VERSION 5.8 ;
BUSBITCHARS "[]" ;
DIVIDERCHAR "/" ;
UNITS
    DATABASE MICRONS 1000 ;
END UNITS

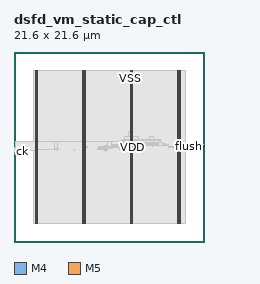
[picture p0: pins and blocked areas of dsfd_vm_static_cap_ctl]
MACRO dsfd_vm_static_cap_ctl
  FOREIGN dsfd_vm_static_cap_ctl 0 0 ;
  CLASS BLOCK ;
  SIZE 21.6 BY 21.6 ;
  PIN ck
    DIRECTION INPUT ;
    USE SIGNAL ;
    PORT
      LAYER M4 ;
        RECT  0 10.32 0.084 10.344 ;
    END
  END ck
  PIN flush
    DIRECTION OUTPUT ;
    USE SIGNAL ;
    PORT
      LAYER M4 ;
        RECT  21.516 10.8 21.6 10.824 ;
    END
  END flush
  PIN rn
    DIRECTION OUTPUT ;
    USE SIGNAL ;
    PORT
      LAYER M4 ;
        RECT  21.516 10.896 21.6 10.92 ;
    END
  END rn
  PIN rst_n
    DIRECTION INPUT ;
    USE SIGNAL ;
    PORT
      LAYER M4 ;
        RECT  0 10.416 0.084 10.44 ;
    END
  END rst_n
  PIN s_flt
    DIRECTION OUTPUT ;
    USE SIGNAL ;
    PORT
      LAYER M4 ;
        RECT  21.516 10.992 21.6 11.016 ;
    END
  END s_flt
  PIN st_drn
    DIRECTION INPUT ;
    USE SIGNAL ;
    PORT
      LAYER M4 ;
        RECT  0 10.512 0.084 10.536 ;
    END
  END st_drn
  PIN st_flt
    DIRECTION INPUT ;
    USE SIGNAL ;
    PORT
      LAYER M4 ;
        RECT  0 10.608 0.084 10.632 ;
    END
  END st_flt
  PIN st_live
    DIRECTION INPUT ;
    USE SIGNAL ;
    PORT
      LAYER M4 ;
        RECT  0 10.704 0.084 10.728 ;
    END
  END st_live
  PIN VDD
    DIRECTION INOUT ;
    USE POWER ;
    PORT
      LAYER M5 ;
        RECT  18.792 2.151 18.912 19.449 ;
        RECT  13.392 2.151 13.512 19.449 ;
        RECT  7.992 2.151 8.112 19.449 ;
        RECT  2.592 2.151 2.712 19.449 ;
    END
  END VDD
  PIN VSS
    DIRECTION INOUT ;
    USE GROUND ;
    PORT
      LAYER M5 ;
        RECT  18.6 2.137 18.72 19.463 ;
        RECT  13.2 2.137 13.32 19.463 ;
        RECT  7.8 2.137 7.92 19.463 ;
        RECT  2.4 2.137 2.52 19.463 ;
    END
  END VSS
  # OT_OBS_CLOSED layer=M5 d_um=1.536 added=0
  OBS
    LAYER RVTN ;
     RECT  2.16 2.16 19.44 2.295 ;
     RECT  2.16 2.565 19.44 2.835 ;
     RECT  2.16 3.105 19.44 3.375 ;
     RECT  2.16 3.645 19.44 3.915 ;
     RECT  2.16 4.185 19.44 4.455 ;
     RECT  2.16 4.725 19.44 4.995 ;
     RECT  2.16 5.265 19.44 5.535 ;
     RECT  2.16 5.805 19.44 6.075 ;
     RECT  2.16 6.345 19.44 6.615 ;
     RECT  2.16 6.885 19.44 7.155 ;
     RECT  2.16 7.425 19.44 7.695 ;
     RECT  2.16 7.965 19.44 8.235 ;
     RECT  2.16 8.505 19.44 8.775 ;
     RECT  2.16 9.045 19.44 9.315 ;
     RECT  2.16 9.585 19.44 9.855 ;
     RECT  2.16 10.125 19.44 10.395 ;
     RECT  2.16 10.665 19.44 10.935 ;
     RECT  2.16 11.205 19.44 11.475 ;
     RECT  2.16 11.745 19.44 12.015 ;
     RECT  2.16 12.285 19.44 12.555 ;
     RECT  2.16 12.825 19.44 13.095 ;
     RECT  2.16 13.365 19.44 13.635 ;
     RECT  2.16 13.905 19.44 14.175 ;
     RECT  2.16 14.445 19.44 14.715 ;
     RECT  2.16 14.985 19.44 15.255 ;
     RECT  2.16 15.525 19.44 15.795 ;
     RECT  2.16 16.065 19.44 16.335 ;
     RECT  2.16 16.605 19.44 16.875 ;
     RECT  2.16 17.145 19.44 17.415 ;
     RECT  2.16 17.685 19.44 17.955 ;
     RECT  2.16 18.225 19.44 18.495 ;
     RECT  2.16 18.765 19.44 19.035 ;
     RECT  2.16 19.305 19.44 19.44 ;
    LAYER RVTP ;
     RECT  2.16 2.295 19.44 2.565 ;
     RECT  2.16 2.835 19.44 3.105 ;
     RECT  2.16 3.375 19.44 3.645 ;
     RECT  2.16 3.915 19.44 4.185 ;
     RECT  2.16 4.455 19.44 4.725 ;
     RECT  2.16 4.995 19.44 5.265 ;
     RECT  2.16 5.535 19.44 5.805 ;
     RECT  2.16 6.075 19.44 6.345 ;
     RECT  2.16 6.615 19.44 6.885 ;
     RECT  2.16 7.155 19.44 7.425 ;
     RECT  2.16 7.695 19.44 7.965 ;
     RECT  2.16 8.235 19.44 8.505 ;
     RECT  2.16 8.775 19.44 9.045 ;
     RECT  2.16 9.315 19.44 9.585 ;
     RECT  2.16 9.855 19.44 10.125 ;
     RECT  2.16 10.395 19.44 10.665 ;
     RECT  2.16 10.935 19.44 11.205 ;
     RECT  2.16 11.475 19.44 11.745 ;
     RECT  2.16 12.015 19.44 12.285 ;
     RECT  2.16 12.555 19.44 12.825 ;
     RECT  2.16 13.095 19.44 13.365 ;
     RECT  2.16 13.635 19.44 13.905 ;
     RECT  2.16 14.175 19.44 14.445 ;
     RECT  2.16 14.715 19.44 14.985 ;
     RECT  2.16 15.255 19.44 15.525 ;
     RECT  2.16 15.795 19.44 16.065 ;
     RECT  2.16 16.335 19.44 16.605 ;
     RECT  2.16 16.875 19.44 17.145 ;
     RECT  2.16 17.415 19.44 17.685 ;
     RECT  2.16 17.955 19.44 18.225 ;
     RECT  2.16 18.495 19.44 18.765 ;
     RECT  2.16 19.035 19.44 19.305 ;
    LAYER M1 ;
     RECT  2.16 2.151 19.44 19.449 ;
    LAYER M2 ;
     RECT  2.16 2.151 19.44 19.449 ;
     RECT  19.44 10.746 20.543 11.034 ;
     RECT  20.543 11.016 21.515 11.034 ;
    LAYER M3 ;
     RECT  2.415 2.143 2.505 2.413 ;
     RECT  7.815 2.143 7.905 2.413 ;
     RECT  13.215 2.143 13.305 2.413 ;
     RECT  18.615 2.143 18.705 2.413 ;
     RECT  13.215 2.413 13.497 10.327 ;
     RECT  10.44 10.327 10.458 10.399 ;
     RECT  13.104 10.327 13.497 10.399 ;
     RECT  2.415 2.413 2.697 10.411 ;
     RECT  10.26 10.399 10.458 10.435 ;
     RECT  2.304 10.411 2.697 10.459 ;
     RECT  4.824 10.435 4.842 10.459 ;
     RECT  4.608 10.459 4.842 10.471 ;
     RECT  10.26 10.435 10.602 10.471 ;
     RECT  13.068 10.399 13.497 10.471 ;
     RECT  2.304 10.459 2.79 10.499 ;
     RECT  6.84 10.363 6.858 10.499 ;
     RECT  4.608 10.471 5.094 10.589 ;
     RECT  11.988 10.471 13.497 10.597 ;
     RECT  2.304 10.499 2.697 10.625 ;
     RECT  9.468 10.471 10.602 10.625 ;
     RECT  9.576 10.625 10.602 10.633 ;
     RECT  4.608 10.589 4.914 10.637 ;
     RECT  9.576 10.633 10.638 10.669 ;
     RECT  7.815 2.413 8.097 10.705 ;
     RECT  11.988 10.597 13.986 10.705 ;
     RECT  9.576 10.669 11.142 10.741 ;
     RECT  11.988 10.705 14.238 10.741 ;
     RECT  18.615 2.413 18.897 10.741 ;
     RECT  9.576 10.741 14.238 10.831 ;
     RECT  7.815 10.705 8.406 10.859 ;
     RECT  17.568 10.741 18.897 10.859 ;
     RECT  20.52 10.741 20.538 10.891 ;
     RECT  4.248 10.699 4.266 10.895 ;
     RECT  9.576 10.831 14.85 10.895 ;
     RECT  10.26 10.895 14.85 10.931 ;
     RECT  20.484 10.891 20.538 10.931 ;
     RECT  15.768 10.831 15.786 10.933 ;
     RECT  15.768 10.933 15.858 10.939 ;
     RECT  17.568 10.859 17.586 10.939 ;
     RECT  15.768 10.939 16.47 10.975 ;
     RECT  17.424 10.939 17.586 10.975 ;
     RECT  18.396 10.859 18.897 10.975 ;
     RECT  10.62 10.931 14.85 11.011 ;
     RECT  15.768 10.975 17.586 11.011 ;
     RECT  20.52 10.931 20.538 11.021 ;
     RECT  21.492 10.795 21.51 11.039 ;
     RECT  10.62 11.011 17.586 11.129 ;
     RECT  18.396 10.975 19.098 11.129 ;
     RECT  10.62 11.129 17.19 11.165 ;
     RECT  11.376 11.165 16.902 11.171 ;
     RECT  12.024 11.171 16.902 11.309 ;
     RECT  18.396 11.129 18.897 11.543 ;
     RECT  12.024 11.309 16.614 11.552 ;
     RECT  12.096 11.552 16.614 11.579 ;
     RECT  12.312 11.579 16.614 11.669 ;
     RECT  12.564 11.669 14.526 11.705 ;
     RECT  15.336 11.669 16.398 11.705 ;
     RECT  15.372 11.705 15.858 11.939 ;
     RECT  12.564 11.705 14.166 11.975 ;
     RECT  15.768 11.939 15.786 11.975 ;
     RECT  12.96 11.975 13.497 12.479 ;
     RECT  13.14 12.479 13.497 12.515 ;
     RECT  2.415 10.625 2.697 19.187 ;
     RECT  7.815 10.859 8.097 19.187 ;
     RECT  13.215 12.515 13.497 19.187 ;
     RECT  18.615 11.543 18.897 19.187 ;
     RECT  2.415 19.187 2.505 19.457 ;
     RECT  7.815 19.187 7.905 19.457 ;
     RECT  13.215 19.187 13.305 19.457 ;
     RECT  18.615 19.187 18.705 19.457 ;
    LAYER M4 ;
     RECT  0.06 10.32 0.133 10.728 ;
     RECT  0.133 10.32 0.179 11.448 ;
     RECT  0.179 10.416 2.408 11.448 ;
     RECT  2.408 2.148 2.512 19.452 ;
     RECT  2.512 2.418 2.704 19.182 ;
     RECT  2.704 10.464 4.637 11.448 ;
     RECT  4.637 10.608 4.925 11.448 ;
     RECT  4.925 11.424 7.808 11.448 ;
     RECT  7.808 2.148 7.912 19.452 ;
     RECT  7.912 2.418 8.104 19.182 ;
     RECT  8.104 11.424 10.573 11.448 ;
     RECT  10.573 10.848 11.081 11.448 ;
     RECT  11.081 11.136 12.013 11.448 ;
     RECT  12.013 11.136 12.125 11.544 ;
     RECT  12.125 11.424 13.208 11.544 ;
     RECT  13.208 2.148 13.312 19.452 ;
     RECT  13.312 2.418 13.504 19.182 ;
     RECT  13.504 11.52 14.465 11.688 ;
     RECT  14.465 11.664 14.537 11.688 ;
     RECT  15.829 10.944 16.477 10.968 ;
     RECT  16.477 10.944 16.913 11.304 ;
     RECT  16.913 10.944 17.453 10.968 ;
     RECT  18.608 2.148 18.712 19.452 ;
     RECT  18.712 2.418 18.904 19.182 ;
     RECT  20.473 10.896 20.509 10.92 ;
     RECT  20.509 10.896 21.481 11.016 ;
     RECT  21.481 10.8 21.564 11.016 ;
    LAYER M5 ;
     RECT  2.4 2.137 2.52 2.151 ;
     RECT  7.8 2.137 7.92 2.151 ;
     RECT  13.2 2.137 13.32 2.151 ;
     RECT  18.6 2.137 18.72 2.151 ;
     RECT  0.144 10.309 0.168 11.459 ;
     RECT  2.4 2.151 2.712 19.449 ;
     RECT  7.8 2.151 8.112 19.449 ;
     RECT  13.2 2.151 13.512 19.449 ;
     RECT  18.6 2.151 18.912 19.449 ;
     RECT  2.4 19.449 2.52 19.463 ;
     RECT  7.8 19.449 7.92 19.463 ;
     RECT  13.2 19.449 13.32 19.463 ;
     RECT  18.6 19.449 18.72 19.463 ;
  END
END dsfd_vm_static_cap_ctl
END LIBRARY
